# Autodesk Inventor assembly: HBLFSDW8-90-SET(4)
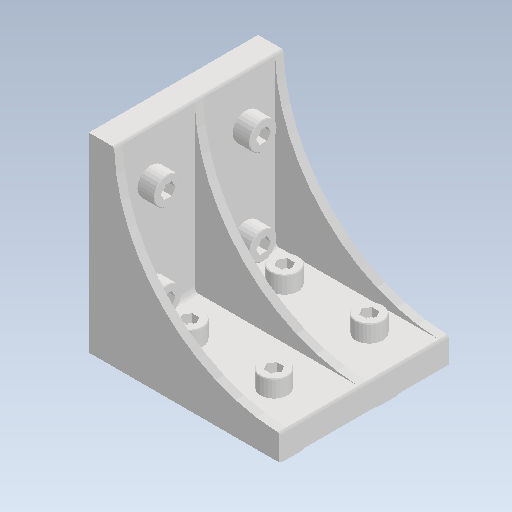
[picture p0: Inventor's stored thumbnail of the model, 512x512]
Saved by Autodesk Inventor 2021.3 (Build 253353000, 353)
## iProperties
Created: 2022-02
Part Number: HBLFSDW8-90-SET(4)
Document SubType Name: Assembly
Designer: kengo
Author: kengo
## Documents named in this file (4)
- C:\Users\kengo\Documents\S2S_frame\SDC345\frame_misumi_ver12\HBLFSDW8-90-SET(4).iam
- C:\Users\kengo\Documents\S2S_frame\SDC345\frame_misumi_ver12\HBLFSDW8-90.ipt
- C:\Users\kengo\Documents\S2S_frame\SDC345\frame_misumi_ver12\HNTT8-8.ipt
- C:\Users\kengo\Documents\S2S_frame\SDC345\frame_misumi_ver12\SCB8-22.ipt
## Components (17 placed, 3 different names)
1. HBLFSDW8-90
2. HNTT8-8
3. SCB8-22
4. HNTT8-8:1
5. SCB8-22:1
6. HNTT8-8:2
7. SCB8-22:2
8. HNTT8-8:3
9. SCB8-22:3
10. HNTT8-8:4
11. SCB8-22:4
12. HNTT8-8:5
13. SCB8-22:5
14. HNTT8-8:6
15. SCB8-22:6
16. HNTT8-8:7
17. SCB8-22:7
